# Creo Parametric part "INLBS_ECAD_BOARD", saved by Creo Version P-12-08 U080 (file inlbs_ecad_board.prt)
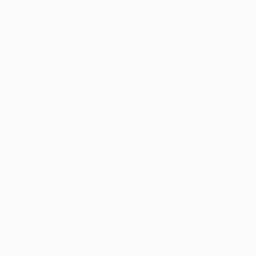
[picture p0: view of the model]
Units: Inch lbm Second (Pro/E Default); INCH, POUND, SECS

Created from: INLBS_PART_SHEETMETAL.PRT

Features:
  1. datum plane "RIGHT"
  2. datum plane "TOP"
  3. datum plane "FRONT"
  4. coordinate system

Other named items: CS0

Surfaces: 3 plane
